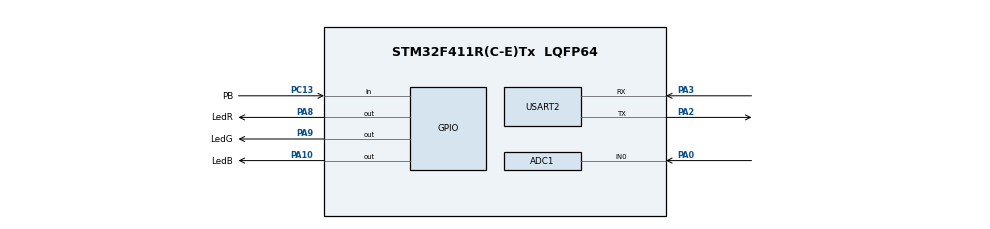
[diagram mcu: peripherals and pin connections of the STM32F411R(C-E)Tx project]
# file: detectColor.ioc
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ADC1.Channel-0\#ChannelRegularConversion=ADC_CHANNEL_0
ADC1.ContinuousConvMode=ENABLE
ADC1.DMAContinuousRequests=ENABLE
ADC1.NbrOfConversionFlag=1
ADC1.Rank-0\#ChannelRegularConversion=1
ADC1.SamplingTime-0\#ChannelRegularConversion=ADC_SAMPLETIME_28CYCLES
ADC1.master=1
Dma.ADC1.0.Direction=DMA_PERIPH_TO_MEMORY
Dma.ADC1.0.FIFOMode=DMA_FIFOMODE_DISABLE
Dma.ADC1.0.Instance=DMA2_Stream0
Dma.ADC1.0.MemDataAlignment=DMA_MDATAALIGN_WORD
Dma.ADC1.0.MemInc=DMA_MINC_ENABLE
Dma.ADC1.0.Mode=DMA_CIRCULAR
Dma.ADC1.0.PeriphDataAlignment=DMA_PDATAALIGN_WORD
Dma.ADC1.0.PeriphInc=DMA_PINC_DISABLE
Dma.ADC1.0.Priority=DMA_PRIORITY_LOW
Dma.Request0=ADC1
Mcu.Family=STM32F4
Mcu.Name=STM32F411R(C-E)Tx
Mcu.Package=LQFP64
NVIC.DMA2_Stream0_IRQn=true\:0\:0\:false\:false\:true\:false\:true\:true
NVIC.PriorityGroup=NVIC_PRIORITYGROUP_4
NVIC.USART2_IRQn=true\:0\:0\:false\:false\:true\:true\:true\:true
PA0-WKUP.Signal=ADCx_IN0
PA10.GPIO_Label=LedB
PA10.Signal=GPIO_Output
PA2.Mode=Asynchronous
PA2.Signal=USART2_TX
PA3.Mode=Asynchronous
PA3.Signal=USART2_RX
PA8.GPIO_Label=LedR
PA8.Signal=GPIO_Output
PA9.GPIO_Label=LedG
PA9.Signal=GPIO_Output
PC13-ANTI_TAMP.GPIO_Label=PB
PC13-ANTI_TAMP.Signal=GPIO_Input
ProjectManager.HeapSize=0x200
ProjectManager.StackSize=0x400
ProjectManager.TargetToolchain=STM32CubeIDE
RCC.AHBFreq_Value=16000000
RCC.APB1Freq_Value=16000000
RCC.APB2Freq_Value=16000000
RCC.CortexFreq_Value=16000000
RCC.HSE_VALUE=25000000
RCC.HSI_VALUE=16000000
RCC.LSE_VALUE=32768
RCC.SYSCLKFreq_VALUE=16000000
RCC.VCOOutputFreq_Value=192000000
SH.ADCx_IN0.0=ADC1_IN0,IN0
TIM11.Prescaler=100-1
USART2.VirtualMode=VM_ASYNC
VP_TIM11_VS_ClockSourceINT.Mode=Enable_Timer
board=custom

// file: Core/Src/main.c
/* USER CODE BEGIN Header */
/**
  ******************************************************************************
  * @file           : main.c
  * @brief          : Main program body
  ******************************************************************************
  * @attention
  *
  * Copyright (c) 2024 STMicroelectronics.
  * All rights reserved.
  *
  * This software is licensed under terms that can be found in the LICENSE file
  * in the root directory of this software component.
  * If no LICENSE file comes with this software, it is provided AS-IS.
  *
  ******************************************************************************
  */
/* USER CODE END Header */
#include "main.h"

/* USER CODE BEGIN Includes */
#include "uart.h"
#include <stdio.h>
#include <stdbool.h>
/* USER CODE END Includes */

ADC_HandleTypeDef hadc1;
DMA_HandleTypeDef hdma_adc1;

TIM_HandleTypeDef htim11;

UART_HandleTypeDef huart2;

void SystemClock_Config(void);
static void MX_GPIO_Init(void);
static void MX_DMA_Init(void);
static void MX_ADC1_Init(void);
static void MX_USART2_UART_Init(void);
static void MX_TIM11_Init(void);

/* USER CODE BEGIN 0 */
uint16_t adcValue;
long map(long x, long in_min, long in_max, long out_min, long out_max) {
  return (x - in_min) * (out_max - out_min) / (in_max - in_min) + out_min;
}

void delayUs (uint16_t time){
	htim11.Instance->CNT = 0;
	while(htim11.Instance->CNT < time);
}

void launchDetectColor(){
   //off led
   HAL_GPIO_WritePin(LedR_GPIO_Port, LedR_Pin, 0);
   HAL_GPIO_WritePin(LedR_GPIO_Port, LedG_Pin, 0);
   HAL_GPIO_WritePin(LedR_GPIO_Port, LedB_Pin, 0);
   //getR
   HAL_GPIO_WritePin(LedR_GPIO_Port, LedR_Pin, 1);
   delayUs(1);
   uint16_t valueR =adcValue;
   HAL_GPIO_WritePin(LedR_GPIO_Port, LedR_Pin, 0);
   //getG
   delayUs(1);
   uint16_t valueG =adcValue;
   HAL_GPIO_WritePin(LedG_GPIO_Port, LedG_Pin, 0);
   //getB
   HAL_GPIO_WritePin(LedB_GPIO_Port, LedB_Pin, 1);
   delayUs(1);
   uint16_t valueB =adcValue;
   HAL_GPIO_WritePin(LedB_GPIO_Port, LedB_Pin, 0);
   printf("%d, %d, %d\n",
  		 map(valueR, 0, 4095, 255, 0),
			 map(valueG, 0, 4095, 255, 0),
			 map(valueB, 0, 4095, 255, 0));
}

/* USER CODE END 0 */

int main(void)
{

  /* MCU Configuration--------------------------------------------------------*/

  /* Reset of all peripherals, Initializes the Flash interface and the Systick. */
  HAL_Init();

  /* Configure the system clock */
  SystemClock_Config();

  /* Initialize all configured peripherals */
  MX_GPIO_Init();
  MX_DMA_Init();
  MX_ADC1_Init();
  MX_USART2_UART_Init();
  MX_TIM11_Init();
  /* USER CODE BEGIN 2 */
  HAL_ADC_Start_DMA(&hadc1, (uint32_t *)&adcValue, 1); //length=adcvalue
  HAL_TIM_Base_Start(&htim11);
  initUart(&huart2);
  /* USER CODE END 2 */

  /* Infinite loop */
  /* USER CODE BEGIN WHILE */
  while (1)
  {
//
//  	static bool oldSwitch, curSwitch;
//     curSwitch = HAL_GPIO_ReadPin(PB_GPIO_Port, PB_Pin);
//     if(oldSwitch != curSwitch){
//        if(curSwitch == 0){
//           launchDetectColor();
//        }
//        oldSwitch = curSwitch;
//     }
//     if(HAL_GPIO_ReadPin(PB_GPIO_Port, PB_Pin)==0)
//        launchDetectColor();
  	launchDetectColor();
  	HAL_Delay(100);
    /* USER CODE END WHILE */

  }
}

void SystemClock_Config(void)
{
  RCC_OscInitTypeDef RCC_OscInitStruct = {0};
  RCC_ClkInitTypeDef RCC_ClkInitStruct = {0};

  /** Configure the main internal regulator output voltage
  */
  __HAL_RCC_PWR_CLK_ENABLE();
  __HAL_PWR_VOLTAGESCALING_CONFIG(PWR_REGULATOR_VOLTAGE_SCALE1);

  /** Initializes the RCC Oscillators according to the specified parameters
  * in the RCC_OscInitTypeDef structure.
  */
  RCC_OscInitStruct.OscillatorType = RCC_OSCILLATORTYPE_HSI;
  RCC_OscInitStruct.HSIState = RCC_HSI_ON;
  RCC_OscInitStruct.HSICalibrationValue = RCC_HSICALIBRATION_DEFAULT;
  RCC_OscInitStruct.PLL.PLLState = RCC_PLL_ON;
  RCC_OscInitStruct.PLL.PLLSource = RCC_PLLSOURCE_HSI;
  RCC_OscInitStruct.PLL.PLLM = 8;
  RCC_OscInitStruct.PLL.PLLN = 100;
  RCC_OscInitStruct.PLL.PLLP = RCC_PLLP_DIV2;
  RCC_OscInitStruct.PLL.PLLQ = 4;
  if (HAL_RCC_OscConfig(&RCC_OscInitStruct) != HAL_OK)
  {
    Error_Handler();
  }

  /** Initializes the CPU, AHB and APB buses clocks
  */
  RCC_ClkInitStruct.ClockType = RCC_CLOCKTYPE_HCLK|RCC_CLOCKTYPE_SYSCLK
                              |RCC_CLOCKTYPE_PCLK1|RCC_CLOCKTYPE_PCLK2;
  RCC_ClkInitStruct.SYSCLKSource = RCC_SYSCLKSOURCE_PLLCLK;
  RCC_ClkInitStruct.AHBCLKDivider = RCC_SYSCLK_DIV1;
  RCC_ClkInitStruct.APB1CLKDivider = RCC_HCLK_DIV2;
  RCC_ClkInitStruct.APB2CLKDivider = RCC_HCLK_DIV1;

  if (HAL_RCC_ClockConfig(&RCC_ClkInitStruct, FLASH_LATENCY_3) != HAL_OK)
  {
    Error_Handler();
  }
}

static void MX_ADC1_Init(void)
{

  ADC_ChannelConfTypeDef sConfig = {0};

  /** Configure the global features of the ADC (Clock, Resolution, Data Alignment and number of conversion)
  */
  hadc1.Instance = ADC1;
  hadc1.Init.ClockPrescaler = ADC_CLOCK_SYNC_PCLK_DIV4;
  hadc1.Init.Resolution = ADC_RESOLUTION_12B;
  hadc1.Init.ScanConvMode = DISABLE;
  hadc1.Init.ContinuousConvMode = ENABLE;
  hadc1.Init.DiscontinuousConvMode = DISABLE;
  hadc1.Init.ExternalTrigConvEdge = ADC_EXTERNALTRIGCONVEDGE_NONE;
  hadc1.Init.ExternalTrigConv = ADC_SOFTWARE_START;
  hadc1.Init.DataAlign = ADC_DATAALIGN_RIGHT;
  hadc1.Init.NbrOfConversion = 1;
  hadc1.Init.DMAContinuousRequests = ENABLE;
  hadc1.Init.EOCSelection = ADC_EOC_SINGLE_CONV;
  if (HAL_ADC_Init(&hadc1) != HAL_OK)
  {
    Error_Handler();
  }

  /** Configure for the selected ADC regular channel its corresponding rank in the sequencer and its sample time.
  */
  sConfig.Channel = ADC_CHANNEL_0;
  sConfig.Rank = 1;
  sConfig.SamplingTime = ADC_SAMPLETIME_28CYCLES;
  if (HAL_ADC_ConfigChannel(&hadc1, &sConfig) != HAL_OK)
  {
    Error_Handler();
  }

}

static void MX_TIM11_Init(void)
{

  htim11.Instance = TIM11;
  htim11.Init.Prescaler = 100-1;
  htim11.Init.CounterMode = TIM_COUNTERMODE_UP;
  htim11.Init.Period = 65535;
  htim11.Init.ClockDivision = TIM_CLOCKDIVISION_DIV1;
  htim11.Init.AutoReloadPreload = TIM_AUTORELOAD_PRELOAD_DISABLE;
  if (HAL_TIM_Base_Init(&htim11) != HAL_OK)
  {
    Error_Handler();
  }

}

static void MX_USART2_UART_Init(void)
{

  huart2.Instance = USART2;
  huart2.Init.BaudRate = 115200;
  huart2.Init.WordLength = UART_WORDLENGTH_8B;
  huart2.Init.StopBits = UART_STOPBITS_1;
  huart2.Init.Parity = UART_PARITY_NONE;
  huart2.Init.Mode = UART_MODE_TX_RX;
  huart2.Init.HwFlowCtl = UART_HWCONTROL_NONE;
  huart2.Init.OverSampling = UART_OVERSAMPLING_16;
  if (HAL_UART_Init(&huart2) != HAL_OK)
  {
    Error_Handler();
  }

}

static void MX_DMA_Init(void)
{

  /* DMA controller clock enable */
  __HAL_RCC_DMA2_CLK_ENABLE();

  /* DMA interrupt init */
  /* DMA2_Stream0_IRQn interrupt configuration */
  HAL_NVIC_SetPriority(DMA2_Stream0_IRQn, 0, 0);
  HAL_NVIC_EnableIRQ(DMA2_Stream0_IRQn);

}

static void MX_GPIO_Init(void)
{
  GPIO_InitTypeDef GPIO_InitStruct = {0};

  /* GPIO Ports Clock Enable */
  __HAL_RCC_GPIOC_CLK_ENABLE();
  __HAL_RCC_GPIOA_CLK_ENABLE();

  /*Configure GPIO pin Output Level */
  HAL_GPIO_WritePin(PB_GPIO_Port, PB_Pin, GPIO_PIN_RESET);

  /*Configure GPIO pin Output Level */
  HAL_GPIO_WritePin(GPIOA, LedR_Pin|LedG_Pin|LedB_Pin, GPIO_PIN_RESET);

  /*Configure GPIO pin : PB_Pin */
  GPIO_InitStruct.Pin = PB_Pin;
  GPIO_InitStruct.Mode = GPIO_MODE_OUTPUT_PP;
  GPIO_InitStruct.Pull = GPIO_NOPULL;
  GPIO_InitStruct.Speed = GPIO_SPEED_FREQ_LOW;
  HAL_GPIO_Init(PB_GPIO_Port, &GPIO_InitStruct);

  /*Configure GPIO pins : LedR_Pin LedG_Pin LedB_Pin */
  GPIO_InitStruct.Pin = LedR_Pin|LedG_Pin|LedB_Pin;
  GPIO_InitStruct.Mode = GPIO_MODE_OUTPUT_PP;
  GPIO_InitStruct.Pull = GPIO_NOPULL;
  GPIO_InitStruct.Speed = GPIO_SPEED_FREQ_LOW;
  HAL_GPIO_Init(GPIOA, &GPIO_InitStruct);

}

void Error_Handler(void)
{
  __disable_irq();
  while (1)
  {
  }
}
